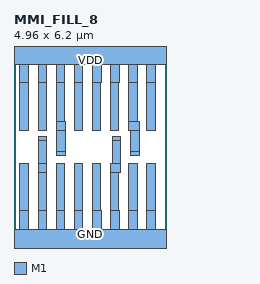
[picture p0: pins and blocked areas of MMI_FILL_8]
MACRO MMI_FILL_8
	CLASS CORE ;
	FOREIGN MMI_FILL_8 0 0 ;
	SIZE 4.96 BY 6.2 ;
	SYMMETRY X Y ;
	SITE CORE1 ;
	PIN GND
		DIRECTION inout ;
		USE GROUND ;
		PORT
			LAYER M1 ;
			RECT 0.79 3.31 1.07 3.445 ;
			LAYER M1 ;
			RECT 3.205 3.31 3.485 3.445 ;
			LAYER M1 ;
			RECT 0.79 2.555 1.075 3.31 ;
			LAYER M1 ;
			RECT 3.2 2.555 3.485 3.31 ;
			LAYER M1 ;
			RECT 0.195 1.02 0.475 2.555 ;
			LAYER M1 ;
			RECT 0.19 0.42 0.475 1.02 ;
			LAYER M1 ;
			RECT 0.785 2.27 1.075 2.555 ;
			LAYER M1 ;
			RECT 0.785 1.02 1.065 2.27 ;
			LAYER M1 ;
			RECT 1.375 1.02 1.655 2.555 ;
			LAYER M1 ;
			RECT 1.965 1.02 2.245 2.555 ;
			LAYER M1 ;
			RECT 2.555 1.02 2.835 2.555 ;
			LAYER M1 ;
			RECT 3.145 2.27 3.485 2.555 ;
			LAYER M1 ;
			RECT 3.145 1.02 3.425 2.27 ;
			LAYER M1 ;
			RECT 3.735 1.02 4.015 2.555 ;
			LAYER M1 ;
			RECT 4.325 1.02 4.605 2.555 ;
			LAYER M1 ;
			RECT 0.785 0.42 1.07 1.02 ;
			LAYER M1 ;
			RECT 1.375 0.42 1.66 1.02 ;
			LAYER M1 ;
			RECT 1.965 0.42 2.25 1.02 ;
			LAYER M1 ;
			RECT 2.555 0.42 2.84 1.02 ;
			LAYER M1 ;
			RECT 3.145 0.42 3.43 1.02 ;
			LAYER M1 ;
			RECT 3.735 0.42 4.02 1.02 ;
			LAYER M1 ;
			RECT 4.325 0.42 4.61 1.02 ;
			LAYER M1 ;
			RECT 0 -0.42 4.96 0.42 ;
		END
	END GND
	PIN VDD
		DIRECTION inout ;
		USE POWER ;
		PORT
			LAYER M1 ;
			RECT 0 5.78 4.96 6.62 ;
			LAYER M1 ;
			RECT 0.19 5.21 0.475 5.78 ;
			LAYER M1 ;
			RECT 0.195 3.645 0.475 5.21 ;
			LAYER M1 ;
			RECT 0.785 5.21 1.07 5.78 ;
			LAYER M1 ;
			RECT 1.375 5.21 1.66 5.78 ;
			LAYER M1 ;
			RECT 1.965 5.21 2.25 5.78 ;
			LAYER M1 ;
			RECT 2.555 5.21 2.84 5.78 ;
			LAYER M1 ;
			RECT 3.145 5.21 3.43 5.78 ;
			LAYER M1 ;
			RECT 3.735 5.21 4.02 5.78 ;
			LAYER M1 ;
			RECT 4.325 5.21 4.61 5.78 ;
			LAYER M1 ;
			RECT 0.785 3.645 1.065 5.21 ;
			LAYER M1 ;
			RECT 1.375 3.93 1.655 5.21 ;
			LAYER M1 ;
			RECT 1.375 3.645 1.675 3.93 ;
			LAYER M1 ;
			RECT 1.965 3.645 2.245 5.21 ;
			LAYER M1 ;
			RECT 2.555 3.645 2.835 5.21 ;
			LAYER M1 ;
			RECT 3.145 3.645 3.425 5.21 ;
			LAYER M1 ;
			RECT 3.735 3.93 4.015 5.21 ;
			LAYER M1 ;
			RECT 3.735 3.645 4.09 3.93 ;
			LAYER M1 ;
			RECT 4.325 3.645 4.605 5.21 ;
			LAYER M1 ;
			RECT 1.39 2.955 1.675 3.645 ;
			LAYER M1 ;
			RECT 1.395 2.835 1.675 2.955 ;
			LAYER M1 ;
			RECT 3.805 2.955 4.09 3.645 ;
			LAYER M1 ;
			RECT 3.805 2.835 4.085 2.955 ;
		END
	END VDD
	OBS
	END
END MMI_FILL_8
